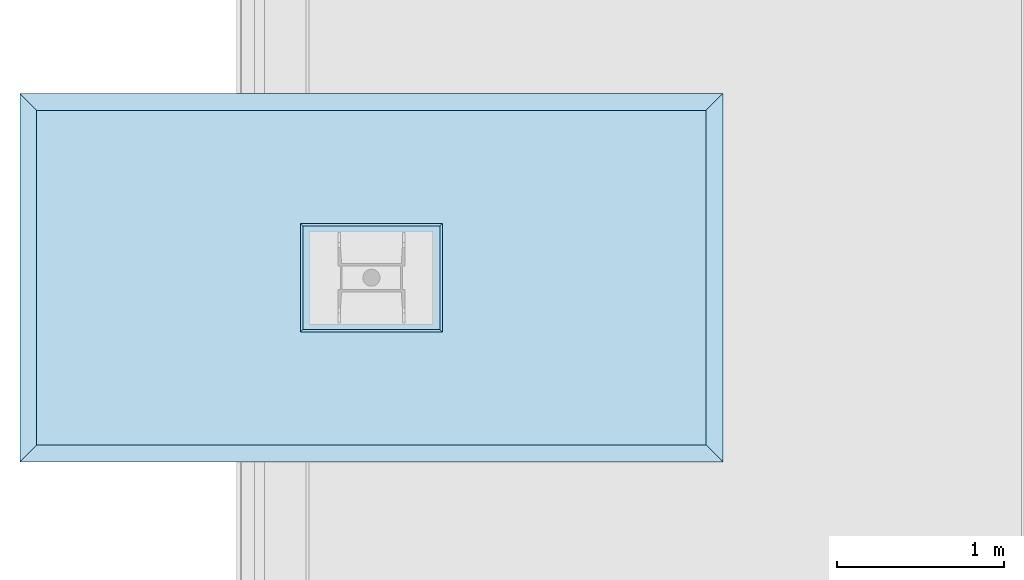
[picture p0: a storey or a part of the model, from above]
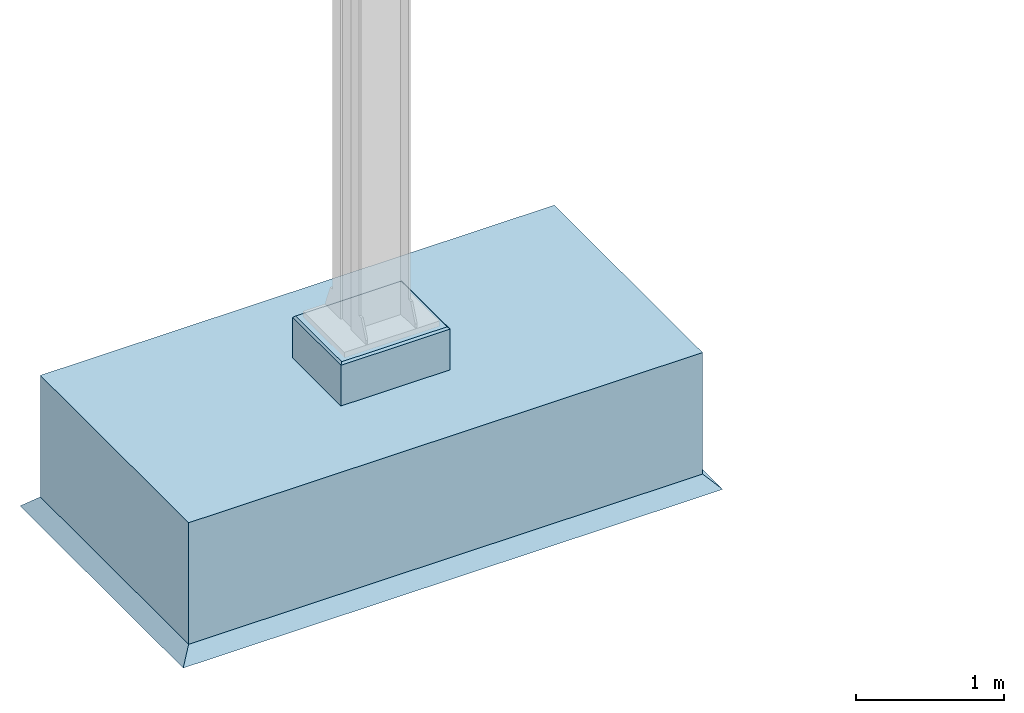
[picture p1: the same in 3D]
Properties of the parts of a building model (IFC4)

# File
Description: ViewDefinition [CoordinationView_V2.0], RevitIdentifiers [ContentGUID: d3ba7735-4996-4f2e-a220-48985317c84a, VersionGUID: 44f114b8-652d-4e34-88d7-4fcb713364eb, NumberOfSaves: 366]
File name: DB_Systemdach_Evolution2020_Typ_4_Ende.ifc
Time: 2026-05-19T18:19:20+01:00
Written by: ODA SDAI 24.6
Made in: Autodesk Revit 24.3.40.26 (DEU) - IFC 24.3.20.0

# IfcSite, Default
RefLatitude: 42, 24, 53, 508911; RefLongitude: -71, -15, -29, -58837; RefElevation: 0 m
Pset_SiteCommon - Reference: Projektinformationen

# IfcBuilding
Pset_BuildingCommon - Reference: Projektinformationen; NumberOfStoreys: 1
Pset_BuildingElementProxyCommon - Reference: Projektinformationen; IsExternal: no
Pset_BuildingStoreyCommon - Reference: Projektinformationen; sets with these values: 2

# IfcBuildingStorey: Ebene:Ebene, DB_Bezugshoehe_max_Bahnsteigkante
LongName: DB_Bezugshoehe_max_Bahnsteigkante; Elevation: 0 m
Pset_BuildingStoreyCommon - Reference: Ebene

# IfcBuildingStorey: Ebene:Hilfsebene PU, Ebene 0
LongName: Ebene 0; Elevation: 0 m
Pset_BuildingStoreyCommon - Reference: Hilfsebene PU

# IfcBuildingElementProxy: DB_Systemdach_Evolution2020_Typ_4_Ende_Dach_o.Fundament:DB_Systemdach_Evolution2020_Typ_4_Ende_Dach_o.Fundament, DB_Systemdach_Evolution2020_Typ_4_Ende_Dach_o.Fundament:DB_Systemdach_Evolution2020_Typ_4_Ende_Dach_o.Fundament:38352835
In: DB_Bezugshoehe_max_Bahnsteigkante
Type - Material: DB_Stahl_pulverbeschichtet_RAL9007, DB_Stahl_pulverbeschichtet_RAL9006
Pset_BuildingElementProxyCommon - Reference: DB_Systemdach_Evolution2020_Typ_4_Ende_Dach_o.Fundament; IsExternal: yes
Pset_EnvironmentalImpactIndicators - Reference: DB_Systemdach_Evolution2020_Typ_4_Ende_Dach_o.Fundament
DB - Objekt: DB Systemdach Evolution2020 Typ 4 Ende; Objektklasse: Bahnsteigdach

# IfcColumn: DB_Systemdach_Stuetze_Typ4:DB_Systemdach_Stuetze_Typ4, DB_Systemdach_Stuetze_Typ4:DB_Systemdach_Stuetze_Typ4:38352836
In: DB_Bezugshoehe_max_Bahnsteigkante
Type - PredefinedType: COLUMN; Material: DB_Stahl_pulverbeschichtet_RAL9007, <Unnamed>
Type - Pset_ColumnCommon - LoadBearing: yes
Type - Pset_ManufacturerTypeInformation - Manufacturer: DB Netze
Pset_ColumnCommon - IsExternal: yes; Reference: DB_Systemdach_Stuetze_Typ4
Pset_EnvironmentalImpactIndicators - Reference: DB_Systemdach_Stuetze_Typ4; sets with these values: 2
DB - Objekt: DB Systemdach Evolution2020 Typ 4 Ende; Objektklasse: Bahnsteigdach

# IfcSlab: DB_Systemdach_Fundament_Typ4:Variante1, DB_Systemdach_Fundament_Typ4:Variante1:38353098
In: DB_Bezugshoehe_max_Bahnsteigkante
Type - PredefinedType: BASESLAB; Material: DB_Ortbeton
Type - Pset_ManufacturerTypeInformation - Manufacturer: DB Netze
Pset_EnvironmentalImpactIndicators - Reference: Variante1; sets with these values: 2
Pset_SlabCommon - IsExternal: yes; Reference: Variante1
DB - Objekt: DB Systemdach Evolution2020 Typ 4 Ende; Objektklasse: Bahnsteigdach
